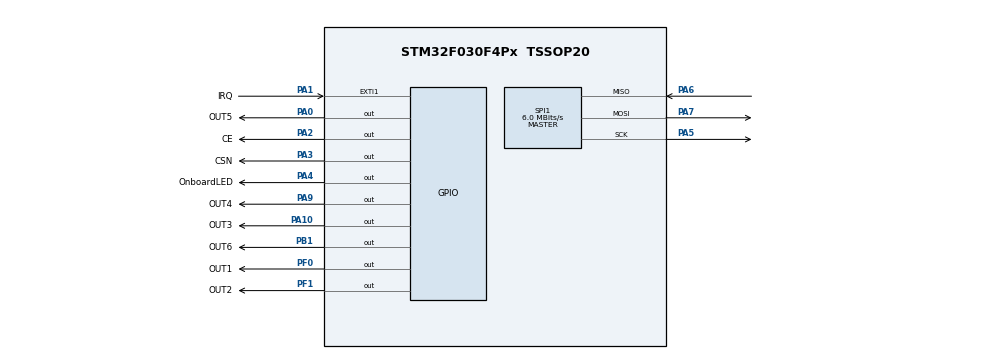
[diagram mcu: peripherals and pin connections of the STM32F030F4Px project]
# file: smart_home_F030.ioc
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Mcu.Family=STM32F0
Mcu.Name=STM32F030F4Px
Mcu.Package=TSSOP20
PA0.GPIO_Label=OUT5
PA0.GPIO_Speed=GPIO_SPEED_FREQ_HIGH
PA0.Signal=GPIO_Output
PA1.GPIO_Label=IRQ
PA1.GPIO_ModeDefaultEXTI=GPIO_MODE_IT_FALLING
PA1.Signal=GPXTI1
PA10.GPIO_Label=OUT3
PA10.GPIO_Speed=GPIO_SPEED_FREQ_HIGH
PA10.Signal=GPIO_Output
PA13.Mode=Serial_Wire
PA13.Signal=SYS_SWDIO
PA14.Mode=Serial_Wire
PA14.Signal=SYS_SWCLK
PA2.GPIO_Label=CE
PA2.GPIO_Speed=GPIO_SPEED_FREQ_HIGH
PA2.Signal=GPIO_Output
PA3.GPIO_Label=CSN
PA3.GPIO_Speed=GPIO_SPEED_FREQ_HIGH
PA3.Signal=GPIO_Output
PA4.GPIO_Label=OnboardLED
PA4.GPIO_Speed=GPIO_SPEED_FREQ_HIGH
PA4.Signal=GPIO_Output
PA5.Mode=Full_Duplex_Master
PA5.Signal=SPI1_SCK
PA6.Mode=Full_Duplex_Master
PA6.Signal=SPI1_MISO
PA7.Mode=Full_Duplex_Master
PA7.Signal=SPI1_MOSI
PA9.GPIO_Label=OUT4
PA9.GPIO_Speed=GPIO_SPEED_FREQ_HIGH
PA9.Signal=GPIO_Output
PB1.GPIO_Label=OUT6
PB1.GPIO_Speed=GPIO_SPEED_FREQ_HIGH
PB1.Signal=GPIO_Output
PF0-OSC_IN.GPIO_Label=OUT1
PF0-OSC_IN.GPIO_Speed=GPIO_SPEED_FREQ_HIGH
PF0-OSC_IN.Signal=GPIO_Output
PF1-OSC_OUT.GPIO_Label=OUT2
PF1-OSC_OUT.GPIO_Speed=GPIO_SPEED_FREQ_HIGH
PF1-OSC_OUT.Signal=GPIO_Output
ProjectManager.HeapSize=0x200
ProjectManager.StackSize=0x400
ProjectManager.TargetToolchain=STM32CubeIDE
RCC.AHBFreq_Value=48000000
RCC.APB1Freq_Value=48000000
RCC.APB1TimFreq_Value=48000000
RCC.HCLKFreq_Value=48000000
RCC.PLLMUL=RCC_PLL_MUL12
RCC.SYSCLKFreq_VALUE=48000000
RCC.SYSCLKSource=RCC_SYSCLKSOURCE_PLLCLK
SPI1.BaudRatePrescaler=SPI_BAUDRATEPRESCALER_8
SPI1.CalculateBaudRate=6.0 MBits/s
SPI1.DataSize=SPI_DATASIZE_8BIT
SPI1.Direction=SPI_DIRECTION_2LINES
SPI1.Mode=SPI_MODE_MASTER
SPI1.NSSPMode=SPI_NSS_PULSE_ENABLE
SPI1.VirtualType=VM_MASTER
board=custom

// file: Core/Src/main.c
/* USER CODE BEGIN Header */
/**
  ******************************************************************************
  * @file           : main.c
  * @brief          : Main program body
  ******************************************************************************
  * @attention
  *
  * <h2><center>&copy; Copyright (c) 2021 STMicroelectronics.
  * All rights reserved.</center></h2>
  *
  * This software component is licensed by ST under BSD 3-Clause license,
  * the "License"; You may not use this file except in compliance with the
  * License. You may obtain a copy of the License at:
  *                        opensource.org/licenses/BSD-3-Clause
  *
  ******************************************************************************
  */
/* USER CODE END Header */
#include "main.h"

/* USER CODE BEGIN Includes */
#include <flash.h>
#include <RF24.h>
/* USER CODE END Includes */

/* USER CODE BEGIN PD */

#define DEVICE_ID 0x01

#define COMMAND_GET_STATUS 0x01
#define COMMAND_SET_STATUS 0x02

#define COMMAND_REPORTING_STATUS 0x00

#define OUTPUTS_COUNT 7

#define FLASH_DATA_ADDR 0x08003800

/* USER CODE END PD */

SPI_HandleTypeDef hspi1;

/* USER CODE BEGIN PV */

GPIO_TypeDef* gpio_ports[OUTPUTS_COUNT] = {
    OnboardLED_GPIO_Port,
    OUT1_GPIO_Port,
    OUT2_GPIO_Port,
    OUT3_GPIO_Port,
    OUT4_GPIO_Port,
    OUT5_GPIO_Port,
    OUT6_GPIO_Port
};

const uint16_t gpio_pins[OUTPUTS_COUNT] = {
    OnboardLED_Pin,
    OUT1_Pin,
    OUT2_Pin,
    OUT3_Pin,
    OUT4_Pin,
    OUT5_Pin,
    OUT6_Pin
};

uint8_t message[32] = {DEVICE_ID, COMMAND_REPORTING_STATUS, OUTPUTS_COUNT, 0x00};

/* USER CODE END PV */

void SystemClock_Config(void);
static void MX_GPIO_Init(void);
static void MX_SPI1_Init(void);

/* USER CODE BEGIN 0 */

void setupOutputs(uint8_t cfg, bool writeFlash) {
  if (message[3] == cfg) {
    return;
  }

  message[3] = cfg;
  for (int i = 0; i < OUTPUTS_COUNT; ++i) {
    HAL_GPIO_WritePin(
        gpio_ports[i],
        gpio_pins[i],
        ((cfg & 0x80) == 0x80) ? GPIO_PIN_SET : GPIO_PIN_RESET
    );
    cfg <<= 1;
  }

  if (writeFlash) {
    flashErase(FLASH_DATA_ADDR);
    flashWriteBegin();
    flashWrite(message + 3, FLASH_DATA_ADDR, 2);
    flashWriteEnd();
  }
}

/* USER CODE END 0 */

int main(void)
{

  /* MCU Configuration--------------------------------------------------------*/

  /* Reset of all peripherals, Initializes the Flash interface and the Systick. */
  HAL_Init();

  /* Configure the system clock */
  SystemClock_Config();

  /* Initialize all configured peripherals */
  MX_GPIO_Init();
  MX_SPI1_Init();
  /* USER CODE BEGIN 2 */

  flashUnlock();
  const uint8_t cfg = *((const volatile uint8_t*)FLASH_DATA_ADDR);
  setupOutputs(cfg, false);

  isChipConnected();  // not checking result because it is often wrong
  NRF_Init();
  setPALevel(RF24_PA_MAX);
  setDataRate(RF24_1MBPS);
  setAddressWidth(5);
  enableDynamicPayloads();
  setAutoAck(true);
  setChannel(103);

  openWritingPipe(0xA83C70FD6CLL);
  openReadingPipe(1, 0xA83C70FD6BLL);
  startListening();

  /* USER CODE END 2 */

  /* Infinite loop */
  /* USER CODE BEGIN WHILE */
  uint8_t buf[32] = {0,};
  uint8_t pipeId = 0;
  while (1) {
    if (available(&pipeId)) {
      if (pipeId == 1) {
        uint8_t length = getDynamicPayloadSize();
        read(buf, length);
        if (length >= 2 && buf[0] == DEVICE_ID) {
          uint8_t command = buf[1];
          switch (command) {
            case COMMAND_GET_STATUS:
              stopListening();
              write(message, 4);
              startListening();
              break;
            case COMMAND_SET_STATUS:
              if (length >= 4 && buf[2] == message[2]) {
                stopListening();
                setupOutputs(buf[3], true);
                write(message, 4);
                startListening();
              }
              break;
          }
        }
      }
    }
    /* USER CODE END WHILE */

  }
}

void SystemClock_Config(void)
{
  RCC_OscInitTypeDef RCC_OscInitStruct = {0};
  RCC_ClkInitTypeDef RCC_ClkInitStruct = {0};

  /** Initializes the RCC Oscillators according to the specified parameters
  * in the RCC_OscInitTypeDef structure.
  */
  RCC_OscInitStruct.OscillatorType = RCC_OSCILLATORTYPE_HSI;
  RCC_OscInitStruct.HSIState = RCC_HSI_ON;
  RCC_OscInitStruct.HSICalibrationValue = RCC_HSICALIBRATION_DEFAULT;
  RCC_OscInitStruct.PLL.PLLState = RCC_PLL_NONE;
  if (HAL_RCC_OscConfig(&RCC_OscInitStruct) != HAL_OK)
  {
    Error_Handler();
  }
  /** Initializes the CPU, AHB and APB buses clocks
  */
  RCC_ClkInitStruct.ClockType = RCC_CLOCKTYPE_HCLK|RCC_CLOCKTYPE_SYSCLK
                              |RCC_CLOCKTYPE_PCLK1;
  RCC_ClkInitStruct.SYSCLKSource = RCC_SYSCLKSOURCE_HSI;
  RCC_ClkInitStruct.AHBCLKDivider = RCC_SYSCLK_DIV1;
  RCC_ClkInitStruct.APB1CLKDivider = RCC_HCLK_DIV1;

  if (HAL_RCC_ClockConfig(&RCC_ClkInitStruct, FLASH_LATENCY_0) != HAL_OK)
  {
    Error_Handler();
  }
}

static void MX_SPI1_Init(void)
{

  /* SPI1 parameter configuration*/
  hspi1.Instance = SPI1;
  hspi1.Init.Mode = SPI_MODE_MASTER;
  hspi1.Init.Direction = SPI_DIRECTION_2LINES;
  hspi1.Init.DataSize = SPI_DATASIZE_8BIT;
  hspi1.Init.CLKPolarity = SPI_POLARITY_LOW;
  hspi1.Init.CLKPhase = SPI_PHASE_1EDGE;
  hspi1.Init.NSS = SPI_NSS_SOFT;
  hspi1.Init.BaudRatePrescaler = SPI_BAUDRATEPRESCALER_2;
  hspi1.Init.FirstBit = SPI_FIRSTBIT_MSB;
  hspi1.Init.TIMode = SPI_TIMODE_DISABLE;
  hspi1.Init.CRCCalculation = SPI_CRCCALCULATION_DISABLE;
  hspi1.Init.CRCPolynomial = 7;
  hspi1.Init.CRCLength = SPI_CRC_LENGTH_DATASIZE;
  hspi1.Init.NSSPMode = SPI_NSS_PULSE_ENABLE;
  if (HAL_SPI_Init(&hspi1) != HAL_OK)
  {
    Error_Handler();
  }

}

static void MX_GPIO_Init(void)
{
  GPIO_InitTypeDef GPIO_InitStruct = {0};

  /* GPIO Ports Clock Enable */
  __HAL_RCC_GPIOF_CLK_ENABLE();
  __HAL_RCC_GPIOA_CLK_ENABLE();
  __HAL_RCC_GPIOB_CLK_ENABLE();

  /*Configure GPIO pin Output Level */
  HAL_GPIO_WritePin(GPIOF, OUT1_Pin|OUT2_Pin, GPIO_PIN_RESET);

  /*Configure GPIO pin Output Level */
  HAL_GPIO_WritePin(GPIOA, OUT5_Pin|CE_Pin|CSN_Pin|OnboardLED_Pin
                          |OUT4_Pin|OUT3_Pin, GPIO_PIN_RESET);

  /*Configure GPIO pin Output Level */
  HAL_GPIO_WritePin(OUT6_GPIO_Port, OUT6_Pin, GPIO_PIN_RESET);

  /*Configure GPIO pins : OUT1_Pin OUT2_Pin */
  GPIO_InitStruct.Pin = OUT1_Pin|OUT2_Pin;
  GPIO_InitStruct.Mode = GPIO_MODE_OUTPUT_PP;
  GPIO_InitStruct.Pull = GPIO_NOPULL;
  GPIO_InitStruct.Speed = GPIO_SPEED_FREQ_LOW;
  HAL_GPIO_Init(GPIOF, &GPIO_InitStruct);

  /*Configure GPIO pins : OUT5_Pin CE_Pin CSN_Pin OnboardLED_Pin
                           OUT4_Pin OUT3_Pin */
  GPIO_InitStruct.Pin = OUT5_Pin|CE_Pin|CSN_Pin|OnboardLED_Pin
                          |OUT4_Pin|OUT3_Pin;
  GPIO_InitStruct.Mode = GPIO_MODE_OUTPUT_PP;
  GPIO_InitStruct.Pull = GPIO_NOPULL;
  GPIO_InitStruct.Speed = GPIO_SPEED_FREQ_LOW;
  HAL_GPIO_Init(GPIOA, &GPIO_InitStruct);

  /*Configure GPIO pin : IRQ_Pin */
  GPIO_InitStruct.Pin = IRQ_Pin;
  GPIO_InitStruct.Mode = GPIO_MODE_IT_FALLING;
  GPIO_InitStruct.Pull = GPIO_NOPULL;
  HAL_GPIO_Init(IRQ_GPIO_Port, &GPIO_InitStruct);

  /*Configure GPIO pin : OUT6_Pin */
  GPIO_InitStruct.Pin = OUT6_Pin;
  GPIO_InitStruct.Mode = GPIO_MODE_OUTPUT_PP;
  GPIO_InitStruct.Pull = GPIO_NOPULL;
  GPIO_InitStruct.Speed = GPIO_SPEED_FREQ_LOW;
  HAL_GPIO_Init(OUT6_GPIO_Port, &GPIO_InitStruct);

}

void Error_Handler(void)
{
  __disable_irq();
  while (1)
  {
  }
}

/************************ (C) COPYRIGHT STMicroelectronics *****END OF FILE****/
